# OpenTallas memory compiler (tools/mem_compiler), ASAP7 abstract view, track-aligned v2 (build_aligned_v2.py)
VERSION 5.7 ;
BUSBITCHARS "[]" ;
DIVIDERCHAR "/" ;
PROPERTYDEFINITIONS
  MACRO width INTEGER ;
  MACRO depth INTEGER ;
  MACRO banks INTEGER ;
END PROPERTYDEFINITIONS
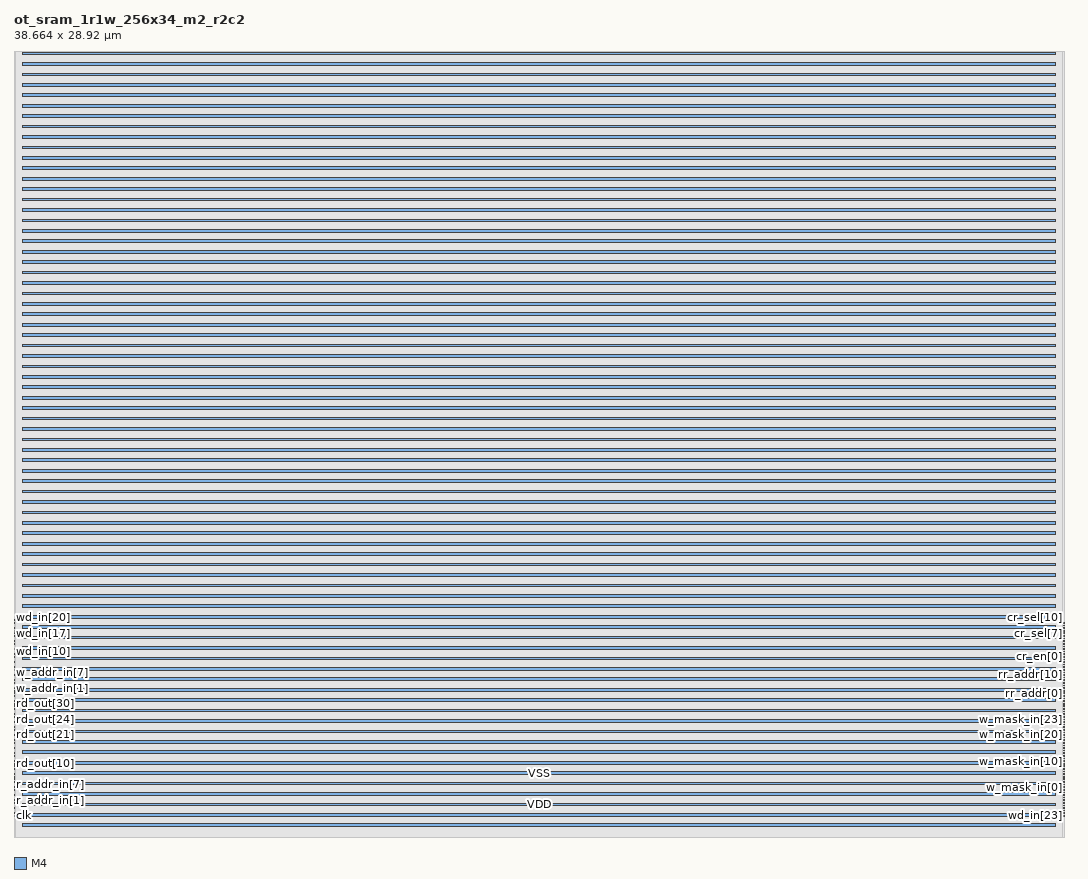
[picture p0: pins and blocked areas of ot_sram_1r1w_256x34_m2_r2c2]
MACRO ot_sram_1r1w_256x34_m2_r2c2
  PROPERTY width 34 ;
  PROPERTY depth 256 ;
  PROPERTY banks 1 ;
  FOREIGN ot_sram_1r1w_256x34_m2_r2c2 0 0 ;
  SYMMETRY X Y ;
  SIZE 38.664 BY 28.920 ;
  CLASS BLOCK ;
  PIN clk
    DIRECTION INPUT ;
    USE CLOCK ;
    SHAPE ABUTMENT ;
    PORT
      LAYER M4 ;
      RECT 0.000 0.768 0.024 0.792 ;
    END
  END clk
  PIN r_ce_in
    DIRECTION INPUT ;
    USE SIGNAL ;
    SHAPE ABUTMENT ;
    PORT
      LAYER M4 ;
      RECT 0.000 0.864 0.024 0.888 ;
    END
  END r_ce_in
  PIN r_addr_in[0]
    DIRECTION INPUT ;
    USE SIGNAL ;
    SHAPE ABUTMENT ;
    PORT
      LAYER M4 ;
      RECT 0.000 0.960 0.024 0.984 ;
    END
  END r_addr_in[0]
  PIN r_addr_in[1]
    DIRECTION INPUT ;
    USE SIGNAL ;
    SHAPE ABUTMENT ;
    PORT
      LAYER M4 ;
      RECT 0.000 1.056 0.024 1.080 ;
    END
  END r_addr_in[1]
  PIN r_addr_in[2]
    DIRECTION INPUT ;
    USE SIGNAL ;
    SHAPE ABUTMENT ;
    PORT
      LAYER M4 ;
      RECT 0.000 1.152 0.024 1.176 ;
    END
  END r_addr_in[2]
  PIN r_addr_in[3]
    DIRECTION INPUT ;
    USE SIGNAL ;
    SHAPE ABUTMENT ;
    PORT
      LAYER M4 ;
      RECT 0.000 1.248 0.024 1.272 ;
    END
  END r_addr_in[3]
  PIN r_addr_in[4]
    DIRECTION INPUT ;
    USE SIGNAL ;
    SHAPE ABUTMENT ;
    PORT
      LAYER M4 ;
      RECT 0.000 1.344 0.024 1.368 ;
    END
  END r_addr_in[4]
  PIN r_addr_in[5]
    DIRECTION INPUT ;
    USE SIGNAL ;
    SHAPE ABUTMENT ;
    PORT
      LAYER M4 ;
      RECT 0.000 1.440 0.024 1.464 ;
    END
  END r_addr_in[5]
  PIN r_addr_in[6]
    DIRECTION INPUT ;
    USE SIGNAL ;
    SHAPE ABUTMENT ;
    PORT
      LAYER M4 ;
      RECT 0.000 1.536 0.024 1.560 ;
    END
  END r_addr_in[6]
  PIN r_addr_in[7]
    DIRECTION INPUT ;
    USE SIGNAL ;
    SHAPE ABUTMENT ;
    PORT
      LAYER M4 ;
      RECT 0.000 1.632 0.024 1.656 ;
    END
  END r_addr_in[7]
  PIN rd_out[0]
    DIRECTION OUTPUT ;
    USE SIGNAL ;
    SHAPE ABUTMENT ;
    PORT
      LAYER M4 ;
      RECT 0.000 1.728 0.024 1.752 ;
    END
  END rd_out[0]
  PIN rd_out[1]
    DIRECTION OUTPUT ;
    USE SIGNAL ;
    SHAPE ABUTMENT ;
    PORT
      LAYER M4 ;
      RECT 0.000 1.824 0.024 1.848 ;
    END
  END rd_out[1]
  PIN rd_out[2]
    DIRECTION OUTPUT ;
    USE SIGNAL ;
    SHAPE ABUTMENT ;
    PORT
      LAYER M4 ;
      RECT 0.000 1.920 0.024 1.944 ;
    END
  END rd_out[2]
  PIN rd_out[3]
    DIRECTION OUTPUT ;
    USE SIGNAL ;
    SHAPE ABUTMENT ;
    PORT
      LAYER M4 ;
      RECT 0.000 2.016 0.024 2.040 ;
    END
  END rd_out[3]
  PIN rd_out[4]
    DIRECTION OUTPUT ;
    USE SIGNAL ;
    SHAPE ABUTMENT ;
    PORT
      LAYER M4 ;
      RECT 0.000 2.112 0.024 2.136 ;
    END
  END rd_out[4]
  PIN rd_out[5]
    DIRECTION OUTPUT ;
    USE SIGNAL ;
    SHAPE ABUTMENT ;
    PORT
      LAYER M4 ;
      RECT 0.000 2.208 0.024 2.232 ;
    END
  END rd_out[5]
  PIN rd_out[6]
    DIRECTION OUTPUT ;
    USE SIGNAL ;
    SHAPE ABUTMENT ;
    PORT
      LAYER M4 ;
      RECT 0.000 2.304 0.024 2.328 ;
    END
  END rd_out[6]
  PIN rd_out[7]
    DIRECTION OUTPUT ;
    USE SIGNAL ;
    SHAPE ABUTMENT ;
    PORT
      LAYER M4 ;
      RECT 0.000 2.400 0.024 2.424 ;
    END
  END rd_out[7]
  PIN rd_out[8]
    DIRECTION OUTPUT ;
    USE SIGNAL ;
    SHAPE ABUTMENT ;
    PORT
      LAYER M4 ;
      RECT 0.000 2.496 0.024 2.520 ;
    END
  END rd_out[8]
  PIN rd_out[9]
    DIRECTION OUTPUT ;
    USE SIGNAL ;
    SHAPE ABUTMENT ;
    PORT
      LAYER M4 ;
      RECT 0.000 2.592 0.024 2.616 ;
    END
  END rd_out[9]
  PIN rd_out[10]
    DIRECTION OUTPUT ;
    USE SIGNAL ;
    SHAPE ABUTMENT ;
    PORT
      LAYER M4 ;
      RECT 0.000 2.688 0.024 2.712 ;
    END
  END rd_out[10]
  PIN rd_out[11]
    DIRECTION OUTPUT ;
    USE SIGNAL ;
    SHAPE ABUTMENT ;
    PORT
      LAYER M4 ;
      RECT 0.000 2.784 0.024 2.808 ;
    END
  END rd_out[11]
  PIN rd_out[12]
    DIRECTION OUTPUT ;
    USE SIGNAL ;
    SHAPE ABUTMENT ;
    PORT
      LAYER M4 ;
      RECT 0.000 2.880 0.024 2.904 ;
    END
  END rd_out[12]
  PIN rd_out[13]
    DIRECTION OUTPUT ;
    USE SIGNAL ;
    SHAPE ABUTMENT ;
    PORT
      LAYER M4 ;
      RECT 0.000 2.976 0.024 3.000 ;
    END
  END rd_out[13]
  PIN rd_out[14]
    DIRECTION OUTPUT ;
    USE SIGNAL ;
    SHAPE ABUTMENT ;
    PORT
      LAYER M4 ;
      RECT 0.000 3.072 0.024 3.096 ;
    END
  END rd_out[14]
  PIN rd_out[15]
    DIRECTION OUTPUT ;
    USE SIGNAL ;
    SHAPE ABUTMENT ;
    PORT
      LAYER M4 ;
      RECT 0.000 3.168 0.024 3.192 ;
    END
  END rd_out[15]
  PIN rd_out[16]
    DIRECTION OUTPUT ;
    USE SIGNAL ;
    SHAPE ABUTMENT ;
    PORT
      LAYER M4 ;
      RECT 0.000 3.264 0.024 3.288 ;
    END
  END rd_out[16]
  PIN rd_out[17]
    DIRECTION OUTPUT ;
    USE SIGNAL ;
    SHAPE ABUTMENT ;
    PORT
      LAYER M4 ;
      RECT 0.000 3.360 0.024 3.384 ;
    END
  END rd_out[17]
  PIN rd_out[18]
    DIRECTION OUTPUT ;
    USE SIGNAL ;
    SHAPE ABUTMENT ;
    PORT
      LAYER M4 ;
      RECT 0.000 3.456 0.024 3.480 ;
    END
  END rd_out[18]
  PIN rd_out[19]
    DIRECTION OUTPUT ;
    USE SIGNAL ;
    SHAPE ABUTMENT ;
    PORT
      LAYER M4 ;
      RECT 0.000 3.552 0.024 3.576 ;
    END
  END rd_out[19]
  PIN rd_out[20]
    DIRECTION OUTPUT ;
    USE SIGNAL ;
    SHAPE ABUTMENT ;
    PORT
      LAYER M4 ;
      RECT 0.000 3.648 0.024 3.672 ;
    END
  END rd_out[20]
  PIN rd_out[21]
    DIRECTION OUTPUT ;
    USE SIGNAL ;
    SHAPE ABUTMENT ;
    PORT
      LAYER M4 ;
      RECT 0.000 3.744 0.024 3.768 ;
    END
  END rd_out[21]
  PIN rd_out[22]
    DIRECTION OUTPUT ;
    USE SIGNAL ;
    SHAPE ABUTMENT ;
    PORT
      LAYER M4 ;
      RECT 0.000 3.840 0.024 3.864 ;
    END
  END rd_out[22]
  PIN rd_out[23]
    DIRECTION OUTPUT ;
    USE SIGNAL ;
    SHAPE ABUTMENT ;
    PORT
      LAYER M4 ;
      RECT 0.000 3.936 0.024 3.960 ;
    END
  END rd_out[23]
  PIN rd_out[24]
    DIRECTION OUTPUT ;
    USE SIGNAL ;
    SHAPE ABUTMENT ;
    PORT
      LAYER M4 ;
      RECT 0.000 4.032 0.024 4.056 ;
    END
  END rd_out[24]
  PIN rd_out[25]
    DIRECTION OUTPUT ;
    USE SIGNAL ;
    SHAPE ABUTMENT ;
    PORT
      LAYER M4 ;
      RECT 0.000 4.128 0.024 4.152 ;
    END
  END rd_out[25]
  PIN rd_out[26]
    DIRECTION OUTPUT ;
    USE SIGNAL ;
    SHAPE ABUTMENT ;
    PORT
      LAYER M4 ;
      RECT 0.000 4.224 0.024 4.248 ;
    END
  END rd_out[26]
  PIN rd_out[27]
    DIRECTION OUTPUT ;
    USE SIGNAL ;
    SHAPE ABUTMENT ;
    PORT
      LAYER M4 ;
      RECT 0.000 4.320 0.024 4.344 ;
    END
  END rd_out[27]
  PIN rd_out[28]
    DIRECTION OUTPUT ;
    USE SIGNAL ;
    SHAPE ABUTMENT ;
    PORT
      LAYER M4 ;
      RECT 0.000 4.416 0.024 4.440 ;
    END
  END rd_out[28]
  PIN rd_out[29]
    DIRECTION OUTPUT ;
    USE SIGNAL ;
    SHAPE ABUTMENT ;
    PORT
      LAYER M4 ;
      RECT 0.000 4.512 0.024 4.536 ;
    END
  END rd_out[29]
  PIN rd_out[30]
    DIRECTION OUTPUT ;
    USE SIGNAL ;
    SHAPE ABUTMENT ;
    PORT
      LAYER M4 ;
      RECT 0.000 4.608 0.024 4.632 ;
    END
  END rd_out[30]
  PIN rd_out[31]
    DIRECTION OUTPUT ;
    USE SIGNAL ;
    SHAPE ABUTMENT ;
    PORT
      LAYER M4 ;
      RECT 0.000 4.704 0.024 4.728 ;
    END
  END rd_out[31]
  PIN rd_out[32]
    DIRECTION OUTPUT ;
    USE SIGNAL ;
    SHAPE ABUTMENT ;
    PORT
      LAYER M4 ;
      RECT 0.000 4.800 0.024 4.824 ;
    END
  END rd_out[32]
  PIN rd_out[33]
    DIRECTION OUTPUT ;
    USE SIGNAL ;
    SHAPE ABUTMENT ;
    PORT
      LAYER M4 ;
      RECT 0.000 4.896 0.024 4.920 ;
    END
  END rd_out[33]
  PIN w_ce_in
    DIRECTION INPUT ;
    USE SIGNAL ;
    SHAPE ABUTMENT ;
    PORT
      LAYER M4 ;
      RECT 0.000 4.992 0.024 5.016 ;
    END
  END w_ce_in
  PIN w_addr_in[0]
    DIRECTION INPUT ;
    USE SIGNAL ;
    SHAPE ABUTMENT ;
    PORT
      LAYER M4 ;
      RECT 0.000 5.088 0.024 5.112 ;
    END
  END w_addr_in[0]
  PIN w_addr_in[1]
    DIRECTION INPUT ;
    USE SIGNAL ;
    SHAPE ABUTMENT ;
    PORT
      LAYER M4 ;
      RECT 0.000 5.184 0.024 5.208 ;
    END
  END w_addr_in[1]
  PIN w_addr_in[2]
    DIRECTION INPUT ;
    USE SIGNAL ;
    SHAPE ABUTMENT ;
    PORT
      LAYER M4 ;
      RECT 0.000 5.280 0.024 5.304 ;
    END
  END w_addr_in[2]
  PIN w_addr_in[3]
    DIRECTION INPUT ;
    USE SIGNAL ;
    SHAPE ABUTMENT ;
    PORT
      LAYER M4 ;
      RECT 0.000 5.376 0.024 5.400 ;
    END
  END w_addr_in[3]
  PIN w_addr_in[4]
    DIRECTION INPUT ;
    USE SIGNAL ;
    SHAPE ABUTMENT ;
    PORT
      LAYER M4 ;
      RECT 0.000 5.472 0.024 5.496 ;
    END
  END w_addr_in[4]
  PIN w_addr_in[5]
    DIRECTION INPUT ;
    USE SIGNAL ;
    SHAPE ABUTMENT ;
    PORT
      LAYER M4 ;
      RECT 0.000 5.568 0.024 5.592 ;
    END
  END w_addr_in[5]
  PIN w_addr_in[6]
    DIRECTION INPUT ;
    USE SIGNAL ;
    SHAPE ABUTMENT ;
    PORT
      LAYER M4 ;
      RECT 0.000 5.664 0.024 5.688 ;
    END
  END w_addr_in[6]
  PIN w_addr_in[7]
    DIRECTION INPUT ;
    USE SIGNAL ;
    SHAPE ABUTMENT ;
    PORT
      LAYER M4 ;
      RECT 0.000 5.760 0.024 5.784 ;
    END
  END w_addr_in[7]
  PIN wd_in[0]
    DIRECTION INPUT ;
    USE SIGNAL ;
    SHAPE ABUTMENT ;
    PORT
      LAYER M4 ;
      RECT 0.000 5.856 0.024 5.880 ;
    END
  END wd_in[0]
  PIN wd_in[1]
    DIRECTION INPUT ;
    USE SIGNAL ;
    SHAPE ABUTMENT ;
    PORT
      LAYER M4 ;
      RECT 0.000 5.952 0.024 5.976 ;
    END
  END wd_in[1]
  PIN wd_in[2]
    DIRECTION INPUT ;
    USE SIGNAL ;
    SHAPE ABUTMENT ;
    PORT
      LAYER M4 ;
      RECT 0.000 6.048 0.024 6.072 ;
    END
  END wd_in[2]
  PIN wd_in[3]
    DIRECTION INPUT ;
    USE SIGNAL ;
    SHAPE ABUTMENT ;
    PORT
      LAYER M4 ;
      RECT 0.000 6.144 0.024 6.168 ;
    END
  END wd_in[3]
  PIN wd_in[4]
    DIRECTION INPUT ;
    USE SIGNAL ;
    SHAPE ABUTMENT ;
    PORT
      LAYER M4 ;
      RECT 0.000 6.240 0.024 6.264 ;
    END
  END wd_in[4]
  PIN wd_in[5]
    DIRECTION INPUT ;
    USE SIGNAL ;
    SHAPE ABUTMENT ;
    PORT
      LAYER M4 ;
      RECT 0.000 6.336 0.024 6.360 ;
    END
  END wd_in[5]
  PIN wd_in[6]
    DIRECTION INPUT ;
    USE SIGNAL ;
    SHAPE ABUTMENT ;
    PORT
      LAYER M4 ;
      RECT 0.000 6.432 0.024 6.456 ;
    END
  END wd_in[6]
  PIN wd_in[7]
    DIRECTION INPUT ;
    USE SIGNAL ;
    SHAPE ABUTMENT ;
    PORT
      LAYER M4 ;
      RECT 0.000 6.528 0.024 6.552 ;
    END
  END wd_in[7]
  PIN wd_in[8]
    DIRECTION INPUT ;
    USE SIGNAL ;
    SHAPE ABUTMENT ;
    PORT
      LAYER M4 ;
      RECT 0.000 6.624 0.024 6.648 ;
    END
  END wd_in[8]
  PIN wd_in[9]
    DIRECTION INPUT ;
    USE SIGNAL ;
    SHAPE ABUTMENT ;
    PORT
      LAYER M4 ;
      RECT 0.000 6.720 0.024 6.744 ;
    END
  END wd_in[9]
  PIN wd_in[10]
    DIRECTION INPUT ;
    USE SIGNAL ;
    SHAPE ABUTMENT ;
    PORT
      LAYER M4 ;
      RECT 0.000 6.816 0.024 6.840 ;
    END
  END wd_in[10]
  PIN wd_in[11]
    DIRECTION INPUT ;
    USE SIGNAL ;
    SHAPE ABUTMENT ;
    PORT
      LAYER M4 ;
      RECT 0.000 6.912 0.024 6.936 ;
    END
  END wd_in[11]
  PIN wd_in[12]
    DIRECTION INPUT ;
    USE SIGNAL ;
    SHAPE ABUTMENT ;
    PORT
      LAYER M4 ;
      RECT 0.000 7.008 0.024 7.032 ;
    END
  END wd_in[12]
  PIN wd_in[13]
    DIRECTION INPUT ;
    USE SIGNAL ;
    SHAPE ABUTMENT ;
    PORT
      LAYER M4 ;
      RECT 0.000 7.104 0.024 7.128 ;
    END
  END wd_in[13]
  PIN wd_in[14]
    DIRECTION INPUT ;
    USE SIGNAL ;
    SHAPE ABUTMENT ;
    PORT
      LAYER M4 ;
      RECT 0.000 7.200 0.024 7.224 ;
    END
  END wd_in[14]
  PIN wd_in[15]
    DIRECTION INPUT ;
    USE SIGNAL ;
    SHAPE ABUTMENT ;
    PORT
      LAYER M4 ;
      RECT 0.000 7.296 0.024 7.320 ;
    END
  END wd_in[15]
  PIN wd_in[16]
    DIRECTION INPUT ;
    USE SIGNAL ;
    SHAPE ABUTMENT ;
    PORT
      LAYER M4 ;
      RECT 0.000 7.392 0.024 7.416 ;
    END
  END wd_in[16]
  PIN wd_in[17]
    DIRECTION INPUT ;
    USE SIGNAL ;
    SHAPE ABUTMENT ;
    PORT
      LAYER M4 ;
      RECT 0.000 7.488 0.024 7.512 ;
    END
  END wd_in[17]
  PIN wd_in[18]
    DIRECTION INPUT ;
    USE SIGNAL ;
    SHAPE ABUTMENT ;
    PORT
      LAYER M4 ;
      RECT 0.000 7.584 0.024 7.608 ;
    END
  END wd_in[18]
  PIN wd_in[19]
    DIRECTION INPUT ;
    USE SIGNAL ;
    SHAPE ABUTMENT ;
    PORT
      LAYER M4 ;
      RECT 0.000 7.680 0.024 7.704 ;
    END
  END wd_in[19]
  PIN wd_in[20]
    DIRECTION INPUT ;
    USE SIGNAL ;
    SHAPE ABUTMENT ;
    PORT
      LAYER M4 ;
      RECT 0.000 7.776 0.024 7.800 ;
    END
  END wd_in[20]
  PIN wd_in[21]
    DIRECTION INPUT ;
    USE SIGNAL ;
    SHAPE ABUTMENT ;
    PORT
      LAYER M4 ;
      RECT 0.000 7.872 0.024 7.896 ;
    END
  END wd_in[21]
  PIN wd_in[22]
    DIRECTION INPUT ;
    USE SIGNAL ;
    SHAPE ABUTMENT ;
    PORT
      LAYER M4 ;
      RECT 0.000 7.968 0.024 7.992 ;
    END
  END wd_in[22]
  PIN wd_in[23]
    DIRECTION INPUT ;
    USE SIGNAL ;
    SHAPE ABUTMENT ;
    PORT
      LAYER M4 ;
      RECT 38.640 0.768 38.664 0.792 ;
    END
  END wd_in[23]
  PIN wd_in[24]
    DIRECTION INPUT ;
    USE SIGNAL ;
    SHAPE ABUTMENT ;
    PORT
      LAYER M4 ;
      RECT 38.640 0.864 38.664 0.888 ;
    END
  END wd_in[24]
  PIN wd_in[25]
    DIRECTION INPUT ;
    USE SIGNAL ;
    SHAPE ABUTMENT ;
    PORT
      LAYER M4 ;
      RECT 38.640 0.960 38.664 0.984 ;
    END
  END wd_in[25]
  PIN wd_in[26]
    DIRECTION INPUT ;
    USE SIGNAL ;
    SHAPE ABUTMENT ;
    PORT
      LAYER M4 ;
      RECT 38.640 1.056 38.664 1.080 ;
    END
  END wd_in[26]
  PIN wd_in[27]
    DIRECTION INPUT ;
    USE SIGNAL ;
    SHAPE ABUTMENT ;
    PORT
      LAYER M4 ;
      RECT 38.640 1.152 38.664 1.176 ;
    END
  END wd_in[27]
  PIN wd_in[28]
    DIRECTION INPUT ;
    USE SIGNAL ;
    SHAPE ABUTMENT ;
    PORT
      LAYER M4 ;
      RECT 38.640 1.248 38.664 1.272 ;
    END
  END wd_in[28]
  PIN wd_in[29]
    DIRECTION INPUT ;
    USE SIGNAL ;
    SHAPE ABUTMENT ;
    PORT
      LAYER M4 ;
      RECT 38.640 1.344 38.664 1.368 ;
    END
  END wd_in[29]
  PIN wd_in[30]
    DIRECTION INPUT ;
    USE SIGNAL ;
    SHAPE ABUTMENT ;
    PORT
      LAYER M4 ;
      RECT 38.640 1.440 38.664 1.464 ;
    END
  END wd_in[30]
  PIN wd_in[31]
    DIRECTION INPUT ;
    USE SIGNAL ;
    SHAPE ABUTMENT ;
    PORT
      LAYER M4 ;
      RECT 38.640 1.536 38.664 1.560 ;
    END
  END wd_in[31]
  PIN wd_in[32]
    DIRECTION INPUT ;
    USE SIGNAL ;
    SHAPE ABUTMENT ;
    PORT
      LAYER M4 ;
      RECT 38.640 1.632 38.664 1.656 ;
    END
  END wd_in[32]
  PIN wd_in[33]
    DIRECTION INPUT ;
    USE SIGNAL ;
    SHAPE ABUTMENT ;
    PORT
      LAYER M4 ;
      RECT 38.640 1.728 38.664 1.752 ;
    END
  END wd_in[33]
  PIN w_mask_in[0]
    DIRECTION INPUT ;
    USE SIGNAL ;
    SHAPE ABUTMENT ;
    PORT
      LAYER M4 ;
      RECT 38.640 1.824 38.664 1.848 ;
    END
  END w_mask_in[0]
  PIN w_mask_in[1]
    DIRECTION INPUT ;
    USE SIGNAL ;
    SHAPE ABUTMENT ;
    PORT
      LAYER M4 ;
      RECT 38.640 1.920 38.664 1.944 ;
    END
  END w_mask_in[1]
  PIN w_mask_in[2]
    DIRECTION INPUT ;
    USE SIGNAL ;
    SHAPE ABUTMENT ;
    PORT
      LAYER M4 ;
      RECT 38.640 2.016 38.664 2.040 ;
    END
  END w_mask_in[2]
  PIN w_mask_in[3]
    DIRECTION INPUT ;
    USE SIGNAL ;
    SHAPE ABUTMENT ;
    PORT
      LAYER M4 ;
      RECT 38.640 2.112 38.664 2.136 ;
    END
  END w_mask_in[3]
  PIN w_mask_in[4]
    DIRECTION INPUT ;
    USE SIGNAL ;
    SHAPE ABUTMENT ;
    PORT
      LAYER M4 ;
      RECT 38.640 2.208 38.664 2.232 ;
    END
  END w_mask_in[4]
  PIN w_mask_in[5]
    DIRECTION INPUT ;
    USE SIGNAL ;
    SHAPE ABUTMENT ;
    PORT
      LAYER M4 ;
      RECT 38.640 2.304 38.664 2.328 ;
    END
  END w_mask_in[5]
  PIN w_mask_in[6]
    DIRECTION INPUT ;
    USE SIGNAL ;
    SHAPE ABUTMENT ;
    PORT
      LAYER M4 ;
      RECT 38.640 2.400 38.664 2.424 ;
    END
  END w_mask_in[6]
  PIN w_mask_in[7]
    DIRECTION INPUT ;
    USE SIGNAL ;
    SHAPE ABUTMENT ;
    PORT
      LAYER M4 ;
      RECT 38.640 2.496 38.664 2.520 ;
    END
  END w_mask_in[7]
  PIN w_mask_in[8]
    DIRECTION INPUT ;
    USE SIGNAL ;
    SHAPE ABUTMENT ;
    PORT
      LAYER M4 ;
      RECT 38.640 2.592 38.664 2.616 ;
    END
  END w_mask_in[8]
  PIN w_mask_in[9]
    DIRECTION INPUT ;
    USE SIGNAL ;
    SHAPE ABUTMENT ;
    PORT
      LAYER M4 ;
      RECT 38.640 2.688 38.664 2.712 ;
    END
  END w_mask_in[9]
  PIN w_mask_in[10]
    DIRECTION INPUT ;
    USE SIGNAL ;
    SHAPE ABUTMENT ;
    PORT
      LAYER M4 ;
      RECT 38.640 2.784 38.664 2.808 ;
    END
  END w_mask_in[10]
  PIN w_mask_in[11]
    DIRECTION INPUT ;
    USE SIGNAL ;
    SHAPE ABUTMENT ;
    PORT
      LAYER M4 ;
      RECT 38.640 2.880 38.664 2.904 ;
    END
  END w_mask_in[11]
  PIN w_mask_in[12]
    DIRECTION INPUT ;
    USE SIGNAL ;
    SHAPE ABUTMENT ;
    PORT
      LAYER M4 ;
      RECT 38.640 2.976 38.664 3.000 ;
    END
  END w_mask_in[12]
  PIN w_mask_in[13]
    DIRECTION INPUT ;
    USE SIGNAL ;
    SHAPE ABUTMENT ;
    PORT
      LAYER M4 ;
      RECT 38.640 3.072 38.664 3.096 ;
    END
  END w_mask_in[13]
  PIN w_mask_in[14]
    DIRECTION INPUT ;
    USE SIGNAL ;
    SHAPE ABUTMENT ;
    PORT
      LAYER M4 ;
      RECT 38.640 3.168 38.664 3.192 ;
    END
  END w_mask_in[14]
  PIN w_mask_in[15]
    DIRECTION INPUT ;
    USE SIGNAL ;
    SHAPE ABUTMENT ;
    PORT
      LAYER M4 ;
      RECT 38.640 3.264 38.664 3.288 ;
    END
  END w_mask_in[15]
  PIN w_mask_in[16]
    DIRECTION INPUT ;
    USE SIGNAL ;
    SHAPE ABUTMENT ;
    PORT
      LAYER M4 ;
      RECT 38.640 3.360 38.664 3.384 ;
    END
  END w_mask_in[16]
  PIN w_mask_in[17]
    DIRECTION INPUT ;
    USE SIGNAL ;
    SHAPE ABUTMENT ;
    PORT
      LAYER M4 ;
      RECT 38.640 3.456 38.664 3.480 ;
    END
  END w_mask_in[17]
  PIN w_mask_in[18]
    DIRECTION INPUT ;
    USE SIGNAL ;
    SHAPE ABUTMENT ;
    PORT
      LAYER M4 ;
      RECT 38.640 3.552 38.664 3.576 ;
    END
  END w_mask_in[18]
  PIN w_mask_in[19]
    DIRECTION INPUT ;
    USE SIGNAL ;
    SHAPE ABUTMENT ;
    PORT
      LAYER M4 ;
      RECT 38.640 3.648 38.664 3.672 ;
    END
  END w_mask_in[19]
  PIN w_mask_in[20]
    DIRECTION INPUT ;
    USE SIGNAL ;
    SHAPE ABUTMENT ;
    PORT
      LAYER M4 ;
      RECT 38.640 3.744 38.664 3.768 ;
    END
  END w_mask_in[20]
  PIN w_mask_in[21]
    DIRECTION INPUT ;
    USE SIGNAL ;
    SHAPE ABUTMENT ;
    PORT
      LAYER M4 ;
      RECT 38.640 3.840 38.664 3.864 ;
    END
  END w_mask_in[21]
  PIN w_mask_in[22]
    DIRECTION INPUT ;
    USE SIGNAL ;
    SHAPE ABUTMENT ;
    PORT
      LAYER M4 ;
      RECT 38.640 3.936 38.664 3.960 ;
    END
  END w_mask_in[22]
  PIN w_mask_in[23]
    DIRECTION INPUT ;
    USE SIGNAL ;
    SHAPE ABUTMENT ;
    PORT
      LAYER M4 ;
      RECT 38.640 4.032 38.664 4.056 ;
    END
  END w_mask_in[23]
  PIN w_mask_in[24]
    DIRECTION INPUT ;
    USE SIGNAL ;
    SHAPE ABUTMENT ;
    PORT
      LAYER M4 ;
      RECT 38.640 4.128 38.664 4.152 ;
    END
  END w_mask_in[24]
  PIN w_mask_in[25]
    DIRECTION INPUT ;
    USE SIGNAL ;
    SHAPE ABUTMENT ;
    PORT
      LAYER M4 ;
      RECT 38.640 4.224 38.664 4.248 ;
    END
  END w_mask_in[25]
  PIN w_mask_in[26]
    DIRECTION INPUT ;
    USE SIGNAL ;
    SHAPE ABUTMENT ;
    PORT
      LAYER M4 ;
      RECT 38.640 4.320 38.664 4.344 ;
    END
  END w_mask_in[26]
  PIN w_mask_in[27]
    DIRECTION INPUT ;
    USE SIGNAL ;
    SHAPE ABUTMENT ;
    PORT
      LAYER M4 ;
      RECT 38.640 4.416 38.664 4.440 ;
    END
  END w_mask_in[27]
  PIN w_mask_in[28]
    DIRECTION INPUT ;
    USE SIGNAL ;
    SHAPE ABUTMENT ;
    PORT
      LAYER M4 ;
      RECT 38.640 4.512 38.664 4.536 ;
    END
  END w_mask_in[28]
  PIN w_mask_in[29]
    DIRECTION INPUT ;
    USE SIGNAL ;
    SHAPE ABUTMENT ;
    PORT
      LAYER M4 ;
      RECT 38.640 4.608 38.664 4.632 ;
    END
  END w_mask_in[29]
  PIN w_mask_in[30]
    DIRECTION INPUT ;
    USE SIGNAL ;
    SHAPE ABUTMENT ;
    PORT
      LAYER M4 ;
      RECT 38.640 4.704 38.664 4.728 ;
    END
  END w_mask_in[30]
  PIN w_mask_in[31]
    DIRECTION INPUT ;
    USE SIGNAL ;
    SHAPE ABUTMENT ;
    PORT
      LAYER M4 ;
      RECT 38.640 4.800 38.664 4.824 ;
    END
  END w_mask_in[31]
  PIN w_mask_in[32]
    DIRECTION INPUT ;
    USE SIGNAL ;
    SHAPE ABUTMENT ;
    PORT
      LAYER M4 ;
      RECT 38.640 4.896 38.664 4.920 ;
    END
  END w_mask_in[32]
  PIN w_mask_in[33]
    DIRECTION INPUT ;
    USE SIGNAL ;
    SHAPE ABUTMENT ;
    PORT
      LAYER M4 ;
      RECT 38.640 4.992 38.664 5.016 ;
    END
  END w_mask_in[33]
  PIN rr_en[0]
    DIRECTION INPUT ;
    USE SIGNAL ;
    SHAPE ABUTMENT ;
    PORT
      LAYER M4 ;
      RECT 38.640 5.088 38.664 5.112 ;
    END
  END rr_en[0]
  PIN rr_en[1]
    DIRECTION INPUT ;
    USE SIGNAL ;
    SHAPE ABUTMENT ;
    PORT
      LAYER M4 ;
      RECT 38.640 5.184 38.664 5.208 ;
    END
  END rr_en[1]
  PIN rr_addr[0]
    DIRECTION INPUT ;
    USE SIGNAL ;
    SHAPE ABUTMENT ;
    PORT
      LAYER M4 ;
      RECT 38.640 5.280 38.664 5.304 ;
    END
  END rr_addr[0]
  PIN rr_addr[1]
    DIRECTION INPUT ;
    USE SIGNAL ;
    SHAPE ABUTMENT ;
    PORT
      LAYER M4 ;
      RECT 38.640 5.376 38.664 5.400 ;
    END
  END rr_addr[1]
  PIN rr_addr[2]
    DIRECTION INPUT ;
    USE SIGNAL ;
    SHAPE ABUTMENT ;
    PORT
      LAYER M4 ;
      RECT 38.640 5.472 38.664 5.496 ;
    END
  END rr_addr[2]
  PIN rr_addr[3]
    DIRECTION INPUT ;
    USE SIGNAL ;
    SHAPE ABUTMENT ;
    PORT
      LAYER M4 ;
      RECT 38.640 5.568 38.664 5.592 ;
    END
  END rr_addr[3]
  PIN rr_addr[4]
    DIRECTION INPUT ;
    USE SIGNAL ;
    SHAPE ABUTMENT ;
    PORT
      LAYER M4 ;
      RECT 38.640 5.664 38.664 5.688 ;
    END
  END rr_addr[4]
  PIN rr_addr[5]
    DIRECTION INPUT ;
    USE SIGNAL ;
    SHAPE ABUTMENT ;
    PORT
      LAYER M4 ;
      RECT 38.640 5.760 38.664 5.784 ;
    END
  END rr_addr[5]
  PIN rr_addr[6]
    DIRECTION INPUT ;
    USE SIGNAL ;
    SHAPE ABUTMENT ;
    PORT
      LAYER M4 ;
      RECT 38.640 5.856 38.664 5.880 ;
    END
  END rr_addr[6]
  PIN rr_addr[7]
    DIRECTION INPUT ;
    USE SIGNAL ;
    SHAPE ABUTMENT ;
    PORT
      LAYER M4 ;
      RECT 38.640 5.952 38.664 5.976 ;
    END
  END rr_addr[7]
  PIN rr_addr[8]
    DIRECTION INPUT ;
    USE SIGNAL ;
    SHAPE ABUTMENT ;
    PORT
      LAYER M4 ;
      RECT 38.640 6.048 38.664 6.072 ;
    END
  END rr_addr[8]
  PIN rr_addr[9]
    DIRECTION INPUT ;
    USE SIGNAL ;
    SHAPE ABUTMENT ;
    PORT
      LAYER M4 ;
      RECT 38.640 6.144 38.664 6.168 ;
    END
  END rr_addr[9]
  PIN rr_addr[10]
    DIRECTION INPUT ;
    USE SIGNAL ;
    SHAPE ABUTMENT ;
    PORT
      LAYER M4 ;
      RECT 38.640 6.240 38.664 6.264 ;
    END
  END rr_addr[10]
  PIN rr_addr[11]
    DIRECTION INPUT ;
    USE SIGNAL ;
    SHAPE ABUTMENT ;
    PORT
      LAYER M4 ;
      RECT 38.640 6.336 38.664 6.360 ;
    END
  END rr_addr[11]
  PIN rr_addr[12]
    DIRECTION INPUT ;
    USE SIGNAL ;
    SHAPE ABUTMENT ;
    PORT
      LAYER M4 ;
      RECT 38.640 6.432 38.664 6.456 ;
    END
  END rr_addr[12]
  PIN rr_addr[13]
    DIRECTION INPUT ;
    USE SIGNAL ;
    SHAPE ABUTMENT ;
    PORT
      LAYER M4 ;
      RECT 38.640 6.528 38.664 6.552 ;
    END
  END rr_addr[13]
  PIN cr_en[0]
    DIRECTION INPUT ;
    USE SIGNAL ;
    SHAPE ABUTMENT ;
    PORT
      LAYER M4 ;
      RECT 38.640 6.624 38.664 6.648 ;
    END
  END cr_en[0]
  PIN cr_en[1]
    DIRECTION INPUT ;
    USE SIGNAL ;
    SHAPE ABUTMENT ;
    PORT
      LAYER M4 ;
      RECT 38.640 6.720 38.664 6.744 ;
    END
  END cr_en[1]
  PIN cr_sel[0]
    DIRECTION INPUT ;
    USE SIGNAL ;
    SHAPE ABUTMENT ;
    PORT
      LAYER M4 ;
      RECT 38.640 6.816 38.664 6.840 ;
    END
  END cr_sel[0]
  PIN cr_sel[1]
    DIRECTION INPUT ;
    USE SIGNAL ;
    SHAPE ABUTMENT ;
    PORT
      LAYER M4 ;
      RECT 38.640 6.912 38.664 6.936 ;
    END
  END cr_sel[1]
  PIN cr_sel[2]
    DIRECTION INPUT ;
    USE SIGNAL ;
    SHAPE ABUTMENT ;
    PORT
      LAYER M4 ;
      RECT 38.640 7.008 38.664 7.032 ;
    END
  END cr_sel[2]
  PIN cr_sel[3]
    DIRECTION INPUT ;
    USE SIGNAL ;
    SHAPE ABUTMENT ;
    PORT
      LAYER M4 ;
      RECT 38.640 7.104 38.664 7.128 ;
    END
  END cr_sel[3]
  PIN cr_sel[4]
    DIRECTION INPUT ;
    USE SIGNAL ;
    SHAPE ABUTMENT ;
    PORT
      LAYER M4 ;
      RECT 38.640 7.200 38.664 7.224 ;
    END
  END cr_sel[4]
  PIN cr_sel[5]
    DIRECTION INPUT ;
    USE SIGNAL ;
    SHAPE ABUTMENT ;
    PORT
      LAYER M4 ;
      RECT 38.640 7.296 38.664 7.320 ;
    END
  END cr_sel[5]
  PIN cr_sel[6]
    DIRECTION INPUT ;
    USE SIGNAL ;
    SHAPE ABUTMENT ;
    PORT
      LAYER M4 ;
      RECT 38.640 7.392 38.664 7.416 ;
    END
  END cr_sel[6]
  PIN cr_sel[7]
    DIRECTION INPUT ;
    USE SIGNAL ;
    SHAPE ABUTMENT ;
    PORT
      LAYER M4 ;
      RECT 38.640 7.488 38.664 7.512 ;
    END
  END cr_sel[7]
  PIN cr_sel[8]
    DIRECTION INPUT ;
    USE SIGNAL ;
    SHAPE ABUTMENT ;
    PORT
      LAYER M4 ;
      RECT 38.640 7.584 38.664 7.608 ;
    END
  END cr_sel[8]
  PIN cr_sel[9]
    DIRECTION INPUT ;
    USE SIGNAL ;
    SHAPE ABUTMENT ;
    PORT
      LAYER M4 ;
      RECT 38.640 7.680 38.664 7.704 ;
    END
  END cr_sel[9]
  PIN cr_sel[10]
    DIRECTION INPUT ;
    USE SIGNAL ;
    SHAPE ABUTMENT ;
    PORT
      LAYER M4 ;
      RECT 38.640 7.776 38.664 7.800 ;
    END
  END cr_sel[10]
  PIN cr_sel[11]
    DIRECTION INPUT ;
    USE SIGNAL ;
    SHAPE ABUTMENT ;
    PORT
      LAYER M4 ;
      RECT 38.640 7.872 38.664 7.896 ;
    END
  END cr_sel[11]
  PIN VDD
    DIRECTION INOUT ;
    USE POWER ;
    PORT
      LAYER M4 ;
      RECT 0.300 0.384 38.364 0.480 ;
      RECT 0.300 1.152 38.364 1.248 ;
      RECT 0.300 1.920 38.364 2.016 ;
      RECT 0.300 2.688 38.364 2.784 ;
      RECT 0.300 3.456 38.364 3.552 ;
      RECT 0.300 4.224 38.364 4.320 ;
      RECT 0.300 4.992 38.364 5.088 ;
      RECT 0.300 5.760 38.364 5.856 ;
      RECT 0.300 6.528 38.364 6.624 ;
      RECT 0.300 7.296 38.364 7.392 ;
      RECT 0.300 8.064 38.364 8.160 ;
      RECT 0.300 8.832 38.364 8.928 ;
      RECT 0.300 9.600 38.364 9.696 ;
      RECT 0.300 10.368 38.364 10.464 ;
      RECT 0.300 11.136 38.364 11.232 ;
      RECT 0.300 11.904 38.364 12.000 ;
      RECT 0.300 12.672 38.364 12.768 ;
      RECT 0.300 13.440 38.364 13.536 ;
      RECT 0.300 14.208 38.364 14.304 ;
      RECT 0.300 14.976 38.364 15.072 ;
      RECT 0.300 15.744 38.364 15.840 ;
      RECT 0.300 16.512 38.364 16.608 ;
      RECT 0.300 17.280 38.364 17.376 ;
      RECT 0.300 18.048 38.364 18.144 ;
      RECT 0.300 18.816 38.364 18.912 ;
      RECT 0.300 19.584 38.364 19.680 ;
      RECT 0.300 20.352 38.364 20.448 ;
      RECT 0.300 21.120 38.364 21.216 ;
      RECT 0.300 21.888 38.364 21.984 ;
      RECT 0.300 22.656 38.364 22.752 ;
      RECT 0.300 23.424 38.364 23.520 ;
      RECT 0.300 24.192 38.364 24.288 ;
      RECT 0.300 24.960 38.364 25.056 ;
      RECT 0.300 25.728 38.364 25.824 ;
      RECT 0.300 26.496 38.364 26.592 ;
      RECT 0.300 27.264 38.364 27.360 ;
      RECT 0.300 28.032 38.364 28.128 ;
      RECT 0.300 28.800 38.364 28.896 ;
    END
  END VDD
  PIN VSS
    DIRECTION INOUT ;
    USE GROUND ;
    PORT
      LAYER M4 ;
      RECT 0.300 0.768 38.364 0.864 ;
      RECT 0.300 1.536 38.364 1.632 ;
      RECT 0.300 2.304 38.364 2.400 ;
      RECT 0.300 3.072 38.364 3.168 ;
      RECT 0.300 3.840 38.364 3.936 ;
      RECT 0.300 4.608 38.364 4.704 ;
      RECT 0.300 5.376 38.364 5.472 ;
      RECT 0.300 6.144 38.364 6.240 ;
      RECT 0.300 6.912 38.364 7.008 ;
      RECT 0.300 7.680 38.364 7.776 ;
      RECT 0.300 8.448 38.364 8.544 ;
      RECT 0.300 9.216 38.364 9.312 ;
      RECT 0.300 9.984 38.364 10.080 ;
      RECT 0.300 10.752 38.364 10.848 ;
      RECT 0.300 11.520 38.364 11.616 ;
      RECT 0.300 12.288 38.364 12.384 ;
      RECT 0.300 13.056 38.364 13.152 ;
      RECT 0.300 13.824 38.364 13.920 ;
      RECT 0.300 14.592 38.364 14.688 ;
      RECT 0.300 15.360 38.364 15.456 ;
      RECT 0.300 16.128 38.364 16.224 ;
      RECT 0.300 16.896 38.364 16.992 ;
      RECT 0.300 17.664 38.364 17.760 ;
      RECT 0.300 18.432 38.364 18.528 ;
      RECT 0.300 19.200 38.364 19.296 ;
      RECT 0.300 19.968 38.364 20.064 ;
      RECT 0.300 20.736 38.364 20.832 ;
      RECT 0.300 21.504 38.364 21.600 ;
      RECT 0.300 22.272 38.364 22.368 ;
      RECT 0.300 23.040 38.364 23.136 ;
      RECT 0.300 23.808 38.364 23.904 ;
      RECT 0.300 24.576 38.364 24.672 ;
      RECT 0.300 25.344 38.364 25.440 ;
      RECT 0.300 26.112 38.364 26.208 ;
      RECT 0.300 26.880 38.364 26.976 ;
      RECT 0.300 27.648 38.364 27.744 ;
      RECT 0.300 28.416 38.364 28.512 ;
    END
  END VSS
  OBS
    LAYER M1 ;
    RECT 0 0 38.664 28.920 ;
    LAYER M2 ;
    RECT 0 0 38.664 28.920 ;
    LAYER M3 ;
    RECT 0 0 38.664 28.920 ;
    LAYER M4 ;
    RECT 0.072 0 38.592 28.920 ;
  END
END ot_sram_1r1w_256x34_m2_r2c2

END LIBRARY
